VERSION 5.7 ;
  NOWIREEXTENSIONATPIN ON ;
  DIVIDERCHAR "/" ;
  BUSBITCHARS "[]" ;
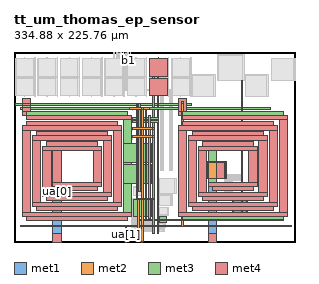
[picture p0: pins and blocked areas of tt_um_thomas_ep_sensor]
MACRO tt_um_thomas_ep_sensor
  CLASS BLOCK ;
  FOREIGN tt_um_thomas_ep_sensor ;
  ORIGIN 0.000 0.000 ;
  SIZE 334.880 BY 225.760 ;
  PIN ua[0]
    PORT
      LAYER met1 ;
        RECT 46.000 0.000 56.000 119.000 ;
        RECT 231.000 0.000 241.000 119.000 ;
      LAYER met2 ;
        RECT 145.000 160.000 147.000 164.000 ;
        RECT 148.000 160.000 150.000 164.000 ;
        RECT 137.000 158.000 161.000 160.000 ;
        RECT 15.000 150.000 135.000 155.000 ;
        RECT 15.000 145.000 140.000 150.000 ;
        RECT 15.000 138.000 123.000 143.000 ;
        RECT 10.000 133.000 128.000 138.000 ;
        RECT 10.000 35.000 20.000 133.000 ;
        RECT 27.000 126.000 111.000 131.000 ;
        RECT 22.000 121.000 116.000 126.000 ;
        RECT 22.000 47.000 32.000 121.000 ;
        RECT 39.000 114.000 99.000 119.000 ;
        RECT 34.000 109.000 104.000 114.000 ;
        RECT 34.000 59.000 44.000 109.000 ;
        RECT 46.000 71.000 56.000 109.000 ;
        RECT 94.000 71.000 104.000 109.000 ;
        RECT 46.000 66.000 104.000 71.000 ;
        RECT 51.000 61.000 99.000 66.000 ;
        RECT 106.000 59.000 116.000 121.000 ;
        RECT 34.000 54.000 116.000 59.000 ;
        RECT 39.000 49.000 111.000 54.000 ;
        RECT 118.000 47.000 128.000 133.000 ;
        RECT 22.000 42.000 128.000 47.000 ;
        RECT 27.000 37.000 123.000 42.000 ;
        RECT 130.000 35.000 140.000 145.000 ;
        RECT 145.000 136.000 147.000 158.000 ;
        RECT 148.000 136.000 150.000 158.000 ;
        RECT 151.000 136.000 153.500 158.000 ;
        RECT 156.000 136.000 158.000 156.000 ;
        RECT 199.000 155.000 201.000 167.000 ;
        RECT 270.000 155.000 272.000 192.000 ;
        RECT 199.000 150.000 320.000 155.000 ;
        RECT 160.000 136.000 162.000 150.000 ;
        RECT 199.000 145.000 325.000 150.000 ;
        RECT 199.000 143.000 201.000 145.000 ;
        RECT 270.000 143.000 272.000 145.000 ;
        RECT 199.000 138.000 308.000 143.000 ;
        RECT 141.000 134.000 167.000 136.000 ;
        RECT 145.000 126.000 147.000 134.000 ;
        RECT 148.000 126.000 150.000 134.000 ;
        RECT 151.000 126.000 153.500 134.000 ;
        RECT 156.000 126.000 158.000 134.000 ;
        RECT 160.000 126.000 162.000 134.000 ;
        RECT 195.000 133.000 313.000 138.000 ;
        RECT 141.000 124.000 167.000 126.000 ;
        RECT 145.000 52.000 147.000 124.000 ;
        RECT 148.000 60.000 150.000 124.000 ;
        RECT 145.000 50.000 149.000 52.000 ;
        RECT 10.000 30.000 140.000 35.000 ;
        RECT 15.000 25.000 135.000 30.000 ;
        RECT 42.000 18.000 60.000 20.000 ;
        RECT 147.000 14.000 149.000 50.000 ;
        RECT 46.000 0.000 56.000 10.000 ;
        RECT 151.000 1.000 153.500 124.000 ;
        RECT 156.000 28.000 158.000 124.000 ;
        RECT 160.000 52.000 162.000 124.000 ;
        RECT 159.000 50.000 167.000 52.000 ;
        RECT 160.000 28.000 162.000 50.000 ;
        RECT 195.000 35.000 205.000 133.000 ;
        RECT 270.000 131.000 272.000 133.000 ;
        RECT 212.000 126.000 296.000 131.000 ;
        RECT 207.000 121.000 301.000 126.000 ;
        RECT 207.000 47.000 217.000 121.000 ;
        RECT 270.000 119.000 272.000 121.000 ;
        RECT 224.000 114.000 284.000 119.000 ;
        RECT 219.000 109.000 289.000 114.000 ;
        RECT 219.000 59.000 229.000 109.000 ;
        RECT 231.000 71.000 241.000 109.000 ;
        RECT 270.000 71.000 272.000 109.000 ;
        RECT 279.000 71.000 289.000 109.000 ;
        RECT 231.000 66.000 289.000 71.000 ;
        RECT 236.000 61.000 284.000 66.000 ;
        RECT 270.000 59.000 272.000 61.000 ;
        RECT 291.000 59.000 301.000 121.000 ;
        RECT 219.000 54.000 301.000 59.000 ;
        RECT 224.000 49.000 296.000 54.000 ;
        RECT 270.000 47.000 272.000 49.000 ;
        RECT 303.000 47.000 313.000 133.000 ;
        RECT 207.000 42.000 313.000 47.000 ;
        RECT 212.000 37.000 308.000 42.000 ;
        RECT 270.000 35.000 272.000 37.000 ;
        RECT 315.000 35.000 325.000 145.000 ;
        RECT 195.000 30.000 325.000 35.000 ;
        RECT 199.000 25.000 320.000 30.000 ;
        RECT 170.000 18.000 198.000 20.000 ;
        RECT 199.000 18.000 201.000 25.000 ;
        RECT 222.000 18.000 240.000 20.000 ;
        RECT 151.810 0.500 152.710 1.000 ;
        RECT 231.000 0.000 241.000 10.000 ;
      LAYER met3 ;
        RECT 199.000 165.000 201.000 167.000 ;
        RECT 10.000 164.000 20.000 165.000 ;
        RECT 2.000 162.000 211.000 164.000 ;
        RECT 10.000 160.000 20.000 162.000 ;
        RECT 8.000 158.000 139.000 160.000 ;
        RECT 151.000 158.000 153.500 160.000 ;
        RECT 159.000 158.000 305.000 160.000 ;
        RECT 15.000 150.000 135.000 155.000 ;
        RECT 200.000 150.000 320.000 155.000 ;
        RECT 15.000 145.000 140.000 150.000 ;
        RECT 141.000 146.000 172.000 148.000 ;
        RECT 200.000 145.000 325.000 150.000 ;
        RECT 15.000 138.000 123.000 143.000 ;
        RECT 10.000 133.000 128.000 138.000 ;
        RECT 10.000 35.000 20.000 133.000 ;
        RECT 27.000 126.000 111.000 131.000 ;
        RECT 22.000 121.000 116.000 126.000 ;
        RECT 22.000 47.000 32.000 121.000 ;
        RECT 39.000 114.000 99.000 119.000 ;
        RECT 34.000 109.000 104.000 114.000 ;
        RECT 34.000 59.000 44.000 109.000 ;
        RECT 46.000 71.000 56.000 109.000 ;
        RECT 94.000 71.000 104.000 109.000 ;
        RECT 46.000 66.000 104.000 71.000 ;
        RECT 51.000 61.000 99.000 66.000 ;
        RECT 106.000 59.000 116.000 121.000 ;
        RECT 34.000 54.000 116.000 59.000 ;
        RECT 39.000 49.000 111.000 54.000 ;
        RECT 118.000 47.000 128.000 133.000 ;
        RECT 22.000 42.000 128.000 47.000 ;
        RECT 130.000 117.400 140.000 145.000 ;
        RECT 141.000 142.000 172.000 144.000 ;
        RECT 200.000 138.000 308.000 143.000 ;
        RECT 165.000 134.000 167.000 136.000 ;
        RECT 195.000 133.000 313.000 138.000 ;
        RECT 165.000 124.000 167.000 126.000 ;
        RECT 130.000 95.000 164.160 117.400 ;
        RECT 130.000 92.400 140.000 95.000 ;
        RECT 130.000 70.000 164.160 92.400 ;
        RECT 27.000 37.000 123.000 42.000 ;
        RECT 130.000 35.000 140.000 70.000 ;
        RECT 147.000 50.600 161.000 52.000 ;
        RECT 10.000 30.000 140.000 35.000 ;
        RECT 142.000 30.000 164.360 50.600 ;
        RECT 165.000 50.000 167.000 52.000 ;
        RECT 195.000 35.000 205.000 133.000 ;
        RECT 212.000 126.000 296.000 131.000 ;
        RECT 207.000 121.000 301.000 126.000 ;
        RECT 207.000 47.000 217.000 121.000 ;
        RECT 224.000 114.000 284.000 119.000 ;
        RECT 219.000 109.000 289.000 114.000 ;
        RECT 219.000 59.000 229.000 109.000 ;
        RECT 231.000 95.400 241.000 109.000 ;
        RECT 230.000 75.000 252.160 95.400 ;
        RECT 231.000 71.000 241.000 75.000 ;
        RECT 279.000 71.000 289.000 109.000 ;
        RECT 231.000 66.000 289.000 71.000 ;
        RECT 236.000 61.000 284.000 66.000 ;
        RECT 291.000 59.000 301.000 121.000 ;
        RECT 219.000 54.000 301.000 59.000 ;
        RECT 224.000 49.000 296.000 54.000 ;
        RECT 260.000 47.000 277.960 49.000 ;
        RECT 303.000 47.000 313.000 133.000 ;
        RECT 207.000 42.000 313.000 47.000 ;
        RECT 212.000 37.000 308.000 42.000 ;
        RECT 260.000 35.000 277.960 37.000 ;
        RECT 315.000 35.000 325.000 145.000 ;
        RECT 15.000 25.000 135.000 30.000 ;
        RECT 173.000 27.000 181.480 30.350 ;
        RECT 195.000 30.000 325.000 35.000 ;
        RECT 200.000 27.000 320.000 30.000 ;
        RECT 148.000 25.000 320.000 27.000 ;
        RECT 173.000 23.630 181.480 25.000 ;
        RECT 8.000 18.000 44.000 20.000 ;
        RECT 58.000 18.000 172.000 20.000 ;
        RECT 196.000 18.000 224.000 20.000 ;
        RECT 238.000 18.000 330.000 20.000 ;
        RECT 46.000 0.000 56.000 10.000 ;
        RECT 132.500 1.000 133.500 18.000 ;
        RECT 132.490 0.500 133.390 1.000 ;
        RECT 151.810 0.500 152.710 1.000 ;
        RECT 231.000 0.000 241.000 10.000 ;
      LAYER met4 ;
        RECT 171.380 217.805 171.900 219.000 ;
        RECT 161.335 197.195 181.945 217.805 ;
        RECT 165.000 194.805 167.000 197.195 ;
        RECT 170.000 194.805 172.000 197.195 ;
        RECT 161.335 174.195 181.945 194.805 ;
        RECT 10.000 155.000 20.000 170.000 ;
        RECT 10.000 150.000 135.000 155.000 ;
        RECT 15.000 145.000 140.000 150.000 ;
        RECT 15.000 138.000 123.000 143.000 ;
        RECT 10.000 133.000 128.000 138.000 ;
        RECT 10.000 35.000 20.000 133.000 ;
        RECT 27.000 126.000 111.000 131.000 ;
        RECT 22.000 121.000 116.000 126.000 ;
        RECT 22.000 47.000 32.000 121.000 ;
        RECT 39.000 114.000 99.000 119.000 ;
        RECT 34.000 109.000 104.000 114.000 ;
        RECT 34.000 59.000 44.000 109.000 ;
        RECT 46.000 71.000 56.000 109.000 ;
        RECT 94.000 71.000 104.000 109.000 ;
        RECT 46.000 66.000 104.000 71.000 ;
        RECT 51.000 61.000 99.000 66.000 ;
        RECT 106.000 59.000 116.000 121.000 ;
        RECT 34.000 54.000 116.000 59.000 ;
        RECT 39.000 49.000 111.000 54.000 ;
        RECT 118.000 47.000 128.000 133.000 ;
        RECT 22.000 42.000 128.000 47.000 ;
        RECT 27.000 37.000 123.000 42.000 ;
        RECT 130.000 35.000 140.000 145.000 ;
        RECT 163.660 95.060 164.140 117.340 ;
        RECT 163.660 70.060 164.140 92.340 ;
        RECT 10.000 30.000 140.000 35.000 ;
        RECT 163.860 30.060 164.340 50.540 ;
        RECT 15.000 25.000 135.000 30.000 ;
        RECT 165.000 10.000 167.000 174.195 ;
        RECT 170.000 10.000 172.000 174.195 ;
        RECT 195.000 155.000 205.000 170.000 ;
        RECT 195.000 150.000 320.000 155.000 ;
        RECT 200.000 145.000 325.000 150.000 ;
        RECT 200.000 138.000 308.000 143.000 ;
        RECT 195.000 133.000 313.000 138.000 ;
        RECT 195.000 35.000 205.000 133.000 ;
        RECT 212.000 126.000 296.000 131.000 ;
        RECT 207.000 121.000 301.000 126.000 ;
        RECT 207.000 47.000 217.000 121.000 ;
        RECT 224.000 114.000 284.000 119.000 ;
        RECT 219.000 109.000 289.000 114.000 ;
        RECT 219.000 59.000 229.000 109.000 ;
        RECT 231.000 95.005 241.000 109.000 ;
        RECT 230.395 75.395 250.005 95.005 ;
        RECT 231.000 71.000 241.000 75.395 ;
        RECT 251.660 75.060 252.140 95.340 ;
        RECT 279.000 71.000 289.000 109.000 ;
        RECT 231.000 66.000 289.000 71.000 ;
        RECT 236.000 61.000 284.000 66.000 ;
        RECT 291.000 59.000 301.000 121.000 ;
        RECT 219.000 54.000 301.000 59.000 ;
        RECT 224.000 49.000 296.000 54.000 ;
        RECT 260.395 47.000 275.805 49.000 ;
        RECT 277.460 47.000 277.940 49.000 ;
        RECT 303.000 47.000 313.000 133.000 ;
        RECT 207.000 42.000 313.000 47.000 ;
        RECT 212.000 37.000 308.000 42.000 ;
        RECT 260.395 35.395 275.805 37.000 ;
        RECT 277.460 35.060 277.940 37.000 ;
        RECT 315.000 35.000 325.000 145.000 ;
        RECT 180.980 23.690 181.460 30.290 ;
        RECT 195.000 30.000 325.000 35.000 ;
        RECT 200.000 25.000 320.000 30.000 ;
        RECT 46.000 0.000 56.000 10.000 ;
        RECT 132.490 0.000 133.390 1.000 ;
        RECT 151.810 0.000 152.710 1.000 ;
        RECT 231.000 0.000 241.000 10.000 ;
    END
  END ua[0]
  PIN ua[1]
    PORT
      LAYER met4 ;
        RECT 132.490 0.000 133.390 1.000 ;
    END
  END ua[1]
  PIN b0
    PORT
      LAYER met4 ;
        RECT 138.310 224.760 138.610 225.760 ;
    END
  END b0
  PIN b1
    PORT
      LAYER met4 ;
        RECT 135.550 224.760 135.850 225.760 ;
    END
  END b1
  PIN b2
    PORT
      LAYER met4 ;
        RECT 132.790 224.760 133.090 225.760 ;
    END
  END b2
  PIN b3
    PORT
      LAYER met4 ;
        RECT 130.030 224.760 130.330 225.760 ;
    END
  END b3
  PIN b4
    PORT
      LAYER met4 ;
        RECT 127.270 224.760 127.570 225.760 ;
    END
  END b4
  PIN b5
    PORT
      LAYER met4 ;
        RECT 124.510 224.760 124.810 225.760 ;
    END
  END b5
  PIN b6
    PORT
      LAYER met4 ;
        RECT 121.750 224.760 122.050 225.760 ;
    END
  END b6
  PIN b7
    PORT
      LAYER met4 ;
        RECT 118.990 224.760 119.290 225.760 ;
    END
  END b7
  OBS
      LAYER pwell ;
        RECT 174.000 85.000 177.590 173.100 ;
        RECT 185.000 85.000 188.590 173.100 ;
        RECT 250.000 73.000 270.870 80.100 ;
        RECT 250.000 60.000 259.570 72.100 ;
        RECT 140.000 12.000 147.100 52.070 ;
        RECT 148.000 12.000 165.470 24.100 ;
      LAYER li1 ;
        RECT 174.180 172.750 177.410 172.920 ;
        RECT 141.000 156.000 141.350 158.160 ;
        RECT 156.770 156.000 157.120 158.160 ;
        RECT 174.180 151.350 174.350 172.750 ;
        RECT 175.390 172.240 175.720 172.410 ;
        RECT 176.350 172.240 176.680 172.410 ;
        RECT 174.750 152.030 174.920 172.070 ;
        RECT 175.230 152.030 175.400 172.070 ;
        RECT 175.710 152.030 175.880 172.070 ;
        RECT 176.190 152.030 176.360 172.070 ;
        RECT 176.670 152.030 176.840 172.070 ;
        RECT 174.910 151.690 175.240 151.860 ;
        RECT 175.870 151.690 176.200 151.860 ;
        RECT 177.240 151.350 177.410 172.750 ;
        RECT 174.180 151.180 177.410 151.350 ;
        RECT 185.180 172.750 188.410 172.920 ;
        RECT 185.180 151.350 185.350 172.750 ;
        RECT 186.390 172.240 186.720 172.410 ;
        RECT 187.350 172.240 187.680 172.410 ;
        RECT 185.750 152.030 185.920 172.070 ;
        RECT 186.230 152.030 186.400 172.070 ;
        RECT 186.710 152.030 186.880 172.070 ;
        RECT 187.190 152.030 187.360 172.070 ;
        RECT 187.670 152.030 187.840 172.070 ;
        RECT 185.910 151.690 186.240 151.860 ;
        RECT 186.870 151.690 187.200 151.860 ;
        RECT 188.240 151.350 188.410 172.750 ;
        RECT 185.180 151.180 188.410 151.350 ;
        RECT 174.180 150.750 177.410 150.920 ;
        RECT 141.000 144.000 141.350 146.160 ;
        RECT 153.450 144.000 153.800 146.160 ;
        RECT 141.000 132.000 141.350 134.160 ;
        RECT 148.470 132.000 148.820 134.160 ;
        RECT 174.180 129.350 174.350 150.750 ;
        RECT 175.390 150.240 175.720 150.410 ;
        RECT 176.350 150.240 176.680 150.410 ;
        RECT 174.750 130.030 174.920 150.070 ;
        RECT 175.230 130.030 175.400 150.070 ;
        RECT 175.710 130.030 175.880 150.070 ;
        RECT 176.190 130.030 176.360 150.070 ;
        RECT 176.670 130.030 176.840 150.070 ;
        RECT 174.910 129.690 175.240 129.860 ;
        RECT 175.870 129.690 176.200 129.860 ;
        RECT 177.240 129.350 177.410 150.750 ;
        RECT 174.180 129.180 177.410 129.350 ;
        RECT 185.180 150.750 188.410 150.920 ;
        RECT 185.180 129.350 185.350 150.750 ;
        RECT 186.390 150.240 186.720 150.410 ;
        RECT 187.350 150.240 187.680 150.410 ;
        RECT 185.750 130.030 185.920 150.070 ;
        RECT 186.230 130.030 186.400 150.070 ;
        RECT 186.710 130.030 186.880 150.070 ;
        RECT 187.190 130.030 187.360 150.070 ;
        RECT 187.670 130.030 187.840 150.070 ;
        RECT 185.910 129.690 186.240 129.860 ;
        RECT 186.870 129.690 187.200 129.860 ;
        RECT 188.240 129.350 188.410 150.750 ;
        RECT 185.180 129.180 188.410 129.350 ;
        RECT 174.180 128.750 177.410 128.920 ;
        RECT 141.000 122.000 141.350 124.160 ;
        RECT 146.810 122.000 147.160 124.160 ;
        RECT 174.180 107.350 174.350 128.750 ;
        RECT 175.390 128.240 175.720 128.410 ;
        RECT 176.350 128.240 176.680 128.410 ;
        RECT 174.750 108.030 174.920 128.070 ;
        RECT 175.230 108.030 175.400 128.070 ;
        RECT 175.710 108.030 175.880 128.070 ;
        RECT 176.190 108.030 176.360 128.070 ;
        RECT 176.670 108.030 176.840 128.070 ;
        RECT 174.910 107.690 175.240 107.860 ;
        RECT 175.870 107.690 176.200 107.860 ;
        RECT 177.240 107.350 177.410 128.750 ;
        RECT 174.180 107.180 177.410 107.350 ;
        RECT 185.180 128.750 188.410 128.920 ;
        RECT 185.180 107.350 185.350 128.750 ;
        RECT 186.390 128.240 186.720 128.410 ;
        RECT 187.350 128.240 187.680 128.410 ;
        RECT 185.750 108.030 185.920 128.070 ;
        RECT 186.230 108.030 186.400 128.070 ;
        RECT 186.710 108.030 186.880 128.070 ;
        RECT 187.190 108.030 187.360 128.070 ;
        RECT 187.670 108.030 187.840 128.070 ;
        RECT 185.910 107.690 186.240 107.860 ;
        RECT 186.870 107.690 187.200 107.860 ;
        RECT 188.240 107.350 188.410 128.750 ;
        RECT 185.180 107.180 188.410 107.350 ;
        RECT 174.180 106.750 177.410 106.920 ;
        RECT 174.180 85.350 174.350 106.750 ;
        RECT 175.390 106.240 175.720 106.410 ;
        RECT 176.350 106.240 176.680 106.410 ;
        RECT 174.750 86.030 174.920 106.070 ;
        RECT 175.230 86.030 175.400 106.070 ;
        RECT 175.710 86.030 175.880 106.070 ;
        RECT 176.190 86.030 176.360 106.070 ;
        RECT 176.670 86.030 176.840 106.070 ;
        RECT 174.910 85.690 175.240 85.860 ;
        RECT 175.870 85.690 176.200 85.860 ;
        RECT 177.240 85.350 177.410 106.750 ;
        RECT 174.180 85.180 177.410 85.350 ;
        RECT 185.180 106.750 188.410 106.920 ;
        RECT 185.180 85.350 185.350 106.750 ;
        RECT 186.390 106.240 186.720 106.410 ;
        RECT 187.350 106.240 187.680 106.410 ;
        RECT 185.750 86.030 185.920 106.070 ;
        RECT 186.230 86.030 186.400 106.070 ;
        RECT 186.710 86.030 186.880 106.070 ;
        RECT 187.190 86.030 187.360 106.070 ;
        RECT 187.670 86.030 187.840 106.070 ;
        RECT 185.910 85.690 186.240 85.860 ;
        RECT 186.870 85.690 187.200 85.860 ;
        RECT 188.240 85.350 188.410 106.750 ;
        RECT 185.180 85.180 188.410 85.350 ;
        RECT 250.180 79.750 270.690 79.920 ;
        RECT 250.180 73.350 250.350 79.750 ;
        RECT 251.390 79.240 251.720 79.410 ;
        RECT 252.350 79.240 252.680 79.410 ;
        RECT 253.310 79.240 253.640 79.410 ;
        RECT 254.270 79.240 254.600 79.410 ;
        RECT 255.230 79.240 255.560 79.410 ;
        RECT 256.190 79.240 256.520 79.410 ;
        RECT 257.150 79.240 257.480 79.410 ;
        RECT 258.110 79.240 258.440 79.410 ;
        RECT 259.070 79.240 259.400 79.410 ;
        RECT 260.030 79.240 260.360 79.410 ;
        RECT 260.990 79.240 261.320 79.410 ;
        RECT 261.950 79.240 262.280 79.410 ;
        RECT 262.910 79.240 263.240 79.410 ;
        RECT 263.870 79.240 264.200 79.410 ;
        RECT 264.830 79.240 265.160 79.410 ;
        RECT 265.790 79.240 266.120 79.410 ;
        RECT 266.750 79.240 267.080 79.410 ;
        RECT 267.710 79.240 268.040 79.410 ;
        RECT 268.670 79.240 269.000 79.410 ;
        RECT 269.630 79.240 269.960 79.410 ;
        RECT 250.750 74.030 250.920 79.070 ;
        RECT 251.230 74.030 251.400 79.070 ;
        RECT 251.710 74.030 251.880 79.070 ;
        RECT 252.190 74.030 252.360 79.070 ;
        RECT 252.670 74.030 252.840 79.070 ;
        RECT 253.150 74.030 253.320 79.070 ;
        RECT 253.630 74.030 253.800 79.070 ;
        RECT 254.110 74.030 254.280 79.070 ;
        RECT 254.590 74.030 254.760 79.070 ;
        RECT 255.070 74.030 255.240 79.070 ;
        RECT 255.550 74.030 255.720 79.070 ;
        RECT 256.030 74.030 256.200 79.070 ;
        RECT 256.510 74.030 256.680 79.070 ;
        RECT 256.990 74.030 257.160 79.070 ;
        RECT 257.470 74.030 257.640 79.070 ;
        RECT 257.950 74.030 258.120 79.070 ;
        RECT 258.430 74.030 258.600 79.070 ;
        RECT 258.910 74.030 259.080 79.070 ;
        RECT 259.390 74.030 259.560 79.070 ;
        RECT 259.870 74.030 260.040 79.070 ;
        RECT 260.350 74.030 260.520 79.070 ;
        RECT 260.830 74.030 261.000 79.070 ;
        RECT 261.310 74.030 261.480 79.070 ;
        RECT 261.790 74.030 261.960 79.070 ;
        RECT 262.270 74.030 262.440 79.070 ;
        RECT 262.750 74.030 262.920 79.070 ;
        RECT 263.230 74.030 263.400 79.070 ;
        RECT 263.710 74.030 263.880 79.070 ;
        RECT 264.190 74.030 264.360 79.070 ;
        RECT 264.670 74.030 264.840 79.070 ;
        RECT 265.150 74.030 265.320 79.070 ;
        RECT 265.630 74.030 265.800 79.070 ;
        RECT 266.110 74.030 266.280 79.070 ;
        RECT 266.590 74.030 266.760 79.070 ;
        RECT 267.070 74.030 267.240 79.070 ;
        RECT 267.550 74.030 267.720 79.070 ;
        RECT 268.030 74.030 268.200 79.070 ;
        RECT 268.510 74.030 268.680 79.070 ;
        RECT 268.990 74.030 269.160 79.070 ;
        RECT 269.470 74.030 269.640 79.070 ;
        RECT 269.950 74.030 270.120 79.070 ;
        RECT 250.910 73.690 251.240 73.860 ;
        RECT 251.870 73.690 252.200 73.860 ;
        RECT 252.830 73.690 253.160 73.860 ;
        RECT 253.790 73.690 254.120 73.860 ;
        RECT 254.750 73.690 255.080 73.860 ;
        RECT 255.710 73.690 256.040 73.860 ;
        RECT 256.670 73.690 257.000 73.860 ;
        RECT 257.630 73.690 257.960 73.860 ;
        RECT 258.590 73.690 258.920 73.860 ;
        RECT 259.550 73.690 259.880 73.860 ;
        RECT 260.510 73.690 260.840 73.860 ;
        RECT 261.470 73.690 261.800 73.860 ;
        RECT 262.430 73.690 262.760 73.860 ;
        RECT 263.390 73.690 263.720 73.860 ;
        RECT 264.350 73.690 264.680 73.860 ;
        RECT 265.310 73.690 265.640 73.860 ;
        RECT 266.270 73.690 266.600 73.860 ;
        RECT 267.230 73.690 267.560 73.860 ;
        RECT 268.190 73.690 268.520 73.860 ;
        RECT 269.150 73.690 269.480 73.860 ;
        RECT 270.520 73.350 270.690 79.750 ;
        RECT 250.180 73.180 270.690 73.350 ;
        RECT 250.180 71.750 259.390 71.920 ;
        RECT 250.180 60.350 250.350 71.750 ;
        RECT 250.980 71.240 251.480 71.410 ;
        RECT 251.770 71.240 252.270 71.410 ;
        RECT 252.560 71.240 253.060 71.410 ;
        RECT 253.350 71.240 253.850 71.410 ;
        RECT 254.140 71.240 254.640 71.410 ;
        RECT 254.930 71.240 255.430 71.410 ;
        RECT 255.720 71.240 256.220 71.410 ;
        RECT 256.510 71.240 257.010 71.410 ;
        RECT 257.300 71.240 257.800 71.410 ;
        RECT 258.090 71.240 258.590 71.410 ;
        RECT 250.750 61.030 250.920 71.070 ;
        RECT 251.540 61.030 251.710 71.070 ;
        RECT 252.330 61.030 252.500 71.070 ;
        RECT 253.120 61.030 253.290 71.070 ;
        RECT 253.910 61.030 254.080 71.070 ;
        RECT 254.700 61.030 254.870 71.070 ;
        RECT 255.490 61.030 255.660 71.070 ;
        RECT 256.280 61.030 256.450 71.070 ;
        RECT 257.070 61.030 257.240 71.070 ;
        RECT 257.860 61.030 258.030 71.070 ;
        RECT 258.650 61.030 258.820 71.070 ;
        RECT 250.980 60.690 251.480 60.860 ;
        RECT 251.770 60.690 252.270 60.860 ;
        RECT 252.560 60.690 253.060 60.860 ;
        RECT 253.350 60.690 253.850 60.860 ;
        RECT 254.140 60.690 254.640 60.860 ;
        RECT 254.930 60.690 255.430 60.860 ;
        RECT 255.720 60.690 256.220 60.860 ;
        RECT 256.510 60.690 257.010 60.860 ;
        RECT 257.300 60.690 257.800 60.860 ;
        RECT 258.090 60.690 258.590 60.860 ;
        RECT 259.220 60.350 259.390 71.750 ;
        RECT 280.000 65.000 280.350 67.160 ;
        RECT 290.790 65.000 291.140 67.160 ;
        RECT 250.180 60.180 259.390 60.350 ;
        RECT 140.180 51.720 146.920 51.890 ;
        RECT 140.180 12.350 140.350 51.720 ;
        RECT 140.690 50.830 140.860 51.160 ;
        RECT 141.030 51.150 146.070 51.320 ;
        RECT 141.030 50.670 146.070 50.840 ;
        RECT 140.690 49.870 140.860 50.200 ;
        RECT 141.030 50.190 146.070 50.360 ;
        RECT 146.240 50.350 146.410 50.680 ;
        RECT 141.030 49.710 146.070 49.880 ;
        RECT 140.690 48.910 140.860 49.240 ;
        RECT 141.030 49.230 146.070 49.400 ;
        RECT 146.240 49.390 146.410 49.720 ;
        RECT 141.030 48.750 146.070 48.920 ;
        RECT 140.690 47.950 140.860 48.280 ;
        RECT 141.030 48.270 146.070 48.440 ;
        RECT 146.240 48.430 146.410 48.760 ;
        RECT 141.030 47.790 146.070 47.960 ;
        RECT 140.690 46.990 140.860 47.320 ;
        RECT 141.030 47.310 146.070 47.480 ;
        RECT 146.240 47.470 146.410 47.800 ;
        RECT 141.030 46.830 146.070 47.000 ;
        RECT 140.690 46.030 140.860 46.360 ;
        RECT 141.030 46.350 146.070 46.520 ;
        RECT 146.240 46.510 146.410 46.840 ;
        RECT 141.030 45.870 146.070 46.040 ;
        RECT 140.690 45.070 140.860 45.400 ;
        RECT 141.030 45.390 146.070 45.560 ;
        RECT 146.240 45.550 146.410 45.880 ;
        RECT 141.030 44.910 146.070 45.080 ;
        RECT 140.690 44.110 140.860 44.440 ;
        RECT 141.030 44.430 146.070 44.600 ;
        RECT 146.240 44.590 146.410 44.920 ;
        RECT 141.030 43.950 146.070 44.120 ;
        RECT 140.690 43.150 140.860 43.480 ;
        RECT 141.030 43.470 146.070 43.640 ;
        RECT 146.240 43.630 146.410 43.960 ;
        RECT 141.030 42.990 146.070 43.160 ;
        RECT 140.690 42.190 140.860 42.520 ;
        RECT 141.030 42.510 146.070 42.680 ;
        RECT 146.240 42.670 146.410 43.000 ;
        RECT 141.030 42.030 146.070 42.200 ;
        RECT 140.690 41.230 140.860 41.560 ;
        RECT 141.030 41.550 146.070 41.720 ;
        RECT 146.240 41.710 146.410 42.040 ;
        RECT 141.030 41.070 146.070 41.240 ;
        RECT 140.690 40.270 140.860 40.600 ;
        RECT 141.030 40.590 146.070 40.760 ;
        RECT 146.240 40.750 146.410 41.080 ;
        RECT 141.030 40.110 146.070 40.280 ;
        RECT 140.690 39.310 140.860 39.640 ;
        RECT 141.030 39.630 146.070 39.800 ;
        RECT 146.240 39.790 146.410 40.120 ;
        RECT 141.030 39.150 146.070 39.320 ;
        RECT 140.690 38.350 140.860 38.680 ;
        RECT 141.030 38.670 146.070 38.840 ;
        RECT 146.240 38.830 146.410 39.160 ;
        RECT 141.030 38.190 146.070 38.360 ;
        RECT 140.690 37.390 140.860 37.720 ;
        RECT 141.030 37.710 146.070 37.880 ;
        RECT 146.240 37.870 146.410 38.200 ;
        RECT 141.030 37.230 146.070 37.400 ;
        RECT 140.690 36.430 140.860 36.760 ;
        RECT 141.030 36.750 146.070 36.920 ;
        RECT 146.240 36.910 146.410 37.240 ;
        RECT 141.030 36.270 146.070 36.440 ;
        RECT 140.690 35.470 140.860 35.800 ;
        RECT 141.030 35.790 146.070 35.960 ;
        RECT 146.240 35.950 146.410 36.280 ;
        RECT 141.030 35.310 146.070 35.480 ;
        RECT 140.690 34.510 140.860 34.840 ;
        RECT 141.030 34.830 146.070 35.000 ;
        RECT 146.240 34.990 146.410 35.320 ;
        RECT 141.030 34.350 146.070 34.520 ;
        RECT 140.690 33.550 140.860 33.880 ;
        RECT 141.030 33.870 146.070 34.040 ;
        RECT 146.240 34.030 146.410 34.360 ;
        RECT 141.030 33.390 146.070 33.560 ;
        RECT 140.690 32.590 140.860 32.920 ;
        RECT 141.030 32.910 146.070 33.080 ;
        RECT 146.240 33.070 146.410 33.400 ;
        RECT 141.030 32.430 146.070 32.600 ;
        RECT 140.690 31.630 140.860 31.960 ;
        RECT 141.030 31.950 146.070 32.120 ;
        RECT 146.240 32.110 146.410 32.440 ;
        RECT 141.030 31.470 146.070 31.640 ;
        RECT 140.690 30.670 140.860 31.000 ;
        RECT 141.030 30.990 146.070 31.160 ;
        RECT 146.240 31.150 146.410 31.480 ;
        RECT 141.030 30.510 146.070 30.680 ;
        RECT 140.690 29.710 140.860 30.040 ;
        RECT 141.030 30.030 146.070 30.200 ;
        RECT 146.240 30.190 146.410 30.520 ;
        RECT 141.030 29.550 146.070 29.720 ;
        RECT 140.690 28.750 140.860 29.080 ;
        RECT 141.030 29.070 146.070 29.240 ;
        RECT 146.240 29.230 146.410 29.560 ;
        RECT 141.030 28.590 146.070 28.760 ;
        RECT 140.690 27.790 140.860 28.120 ;
        RECT 141.030 28.110 146.070 28.280 ;
        RECT 146.240 28.270 146.410 28.600 ;
        RECT 141.030 27.630 146.070 27.800 ;
        RECT 140.690 26.830 140.860 27.160 ;
        RECT 141.030 27.150 146.070 27.320 ;
        RECT 146.240 27.310 146.410 27.640 ;
        RECT 141.030 26.670 146.070 26.840 ;
        RECT 140.690 25.870 140.860 26.200 ;
        RECT 141.030 26.190 146.070 26.360 ;
        RECT 146.240 26.350 146.410 26.680 ;
        RECT 141.030 25.710 146.070 25.880 ;
        RECT 140.690 24.910 140.860 25.240 ;
        RECT 141.030 25.230 146.070 25.400 ;
        RECT 146.240 25.390 146.410 25.720 ;
        RECT 141.030 24.750 146.070 24.920 ;
        RECT 140.690 23.950 140.860 24.280 ;
        RECT 141.030 24.270 146.070 24.440 ;
        RECT 146.240 24.430 146.410 24.760 ;
        RECT 141.030 23.790 146.070 23.960 ;
        RECT 140.690 22.990 140.860 23.320 ;
        RECT 141.030 23.310 146.070 23.480 ;
        RECT 146.240 23.470 146.410 23.800 ;
        RECT 141.030 22.830 146.070 23.000 ;
        RECT 140.690 22.030 140.860 22.360 ;
        RECT 141.030 22.350 146.070 22.520 ;
        RECT 146.240 22.510 146.410 22.840 ;
        RECT 141.030 21.870 146.070 22.040 ;
        RECT 140.690 21.070 140.860 21.400 ;
        RECT 141.030 21.390 146.070 21.560 ;
        RECT 146.240 21.550 146.410 21.880 ;
        RECT 141.030 20.910 146.070 21.080 ;
        RECT 140.690 20.110 140.860 20.440 ;
        RECT 141.030 20.430 146.070 20.600 ;
        RECT 146.240 20.590 146.410 20.920 ;
        RECT 141.030 19.950 146.070 20.120 ;
        RECT 140.690 19.150 140.860 19.480 ;
        RECT 141.030 19.470 146.070 19.640 ;
        RECT 146.240 19.630 146.410 19.960 ;
        RECT 141.030 18.990 146.070 19.160 ;
        RECT 140.690 18.190 140.860 18.520 ;
        RECT 141.030 18.510 146.070 18.680 ;
        RECT 146.240 18.670 146.410 19.000 ;
        RECT 141.030 18.030 146.070 18.200 ;
        RECT 140.690 17.230 140.860 17.560 ;
        RECT 141.030 17.550 146.070 17.720 ;
        RECT 146.240 17.710 146.410 18.040 ;
        RECT 141.030 17.070 146.070 17.240 ;
        RECT 140.690 16.270 140.860 16.600 ;
        RECT 141.030 16.590 146.070 16.760 ;
        RECT 146.240 16.750 146.410 17.080 ;
        RECT 141.030 16.110 146.070 16.280 ;
        RECT 140.690 15.310 140.860 15.640 ;
        RECT 141.030 15.630 146.070 15.800 ;
        RECT 146.240 15.790 146.410 16.120 ;
        RECT 141.030 15.150 146.070 15.320 ;
        RECT 140.690 14.350 140.860 14.680 ;
        RECT 141.030 14.670 146.070 14.840 ;
        RECT 146.240 14.830 146.410 15.160 ;
        RECT 141.030 14.190 146.070 14.360 ;
        RECT 140.690 13.390 140.860 13.720 ;
        RECT 141.030 13.710 146.070 13.880 ;
        RECT 146.240 13.870 146.410 14.200 ;
        RECT 141.030 13.230 146.070 13.400 ;
        RECT 141.030 12.750 146.070 12.920 ;
        RECT 146.240 12.910 146.410 13.240 ;
        RECT 146.750 12.350 146.920 51.720 ;
        RECT 280.000 50.000 280.350 52.160 ;
        RECT 292.450 50.000 292.800 52.160 ;
        RECT 140.180 12.180 146.920 12.350 ;
        RECT 148.180 23.750 165.290 23.920 ;
        RECT 148.180 12.350 148.350 23.750 ;
        RECT 148.980 23.240 149.480 23.410 ;
        RECT 149.770 23.240 150.270 23.410 ;
        RECT 150.560 23.240 151.060 23.410 ;
        RECT 151.350 23.240 151.850 23.410 ;
        RECT 152.140 23.240 152.640 23.410 ;
        RECT 152.930 23.240 153.430 23.410 ;
        RECT 153.720 23.240 154.220 23.410 ;
        RECT 154.510 23.240 155.010 23.410 ;
        RECT 155.300 23.240 155.800 23.410 ;
        RECT 156.090 23.240 156.590 23.410 ;
        RECT 156.880 23.240 157.380 23.410 ;
        RECT 157.670 23.240 158.170 23.410 ;
        RECT 158.460 23.240 158.960 23.410 ;
        RECT 159.250 23.240 159.750 23.410 ;
        RECT 160.040 23.240 160.540 23.410 ;
        RECT 160.830 23.240 161.330 23.410 ;
        RECT 161.620 23.240 162.120 23.410 ;
        RECT 162.410 23.240 162.910 23.410 ;
        RECT 163.200 23.240 163.700 23.410 ;
        RECT 163.990 23.240 164.490 23.410 ;
        RECT 148.750 13.030 148.920 23.070 ;
        RECT 149.540 13.030 149.710 23.070 ;
        RECT 150.330 13.030 150.500 23.070 ;
        RECT 151.120 13.030 151.290 23.070 ;
        RECT 151.910 13.030 152.080 23.070 ;
        RECT 152.700 13.030 152.870 23.070 ;
        RECT 153.490 13.030 153.660 23.070 ;
        RECT 154.280 13.030 154.450 23.070 ;
        RECT 155.070 13.030 155.240 23.070 ;
        RECT 155.860 13.030 156.030 23.070 ;
        RECT 156.650 13.030 156.820 23.070 ;
        RECT 157.440 13.030 157.610 23.070 ;
        RECT 158.230 13.030 158.400 23.070 ;
        RECT 159.020 13.030 159.190 23.070 ;
        RECT 159.810 13.030 159.980 23.070 ;
        RECT 160.600 13.030 160.770 23.070 ;
        RECT 161.390 13.030 161.560 23.070 ;
        RECT 162.180 13.030 162.350 23.070 ;
        RECT 162.970 13.030 163.140 23.070 ;
        RECT 163.760 13.030 163.930 23.070 ;
        RECT 164.550 13.030 164.720 23.070 ;
        RECT 148.980 12.690 149.480 12.860 ;
        RECT 149.770 12.690 150.270 12.860 ;
        RECT 150.560 12.690 151.060 12.860 ;
        RECT 151.350 12.690 151.850 12.860 ;
        RECT 152.140 12.690 152.640 12.860 ;
        RECT 152.930 12.690 153.430 12.860 ;
        RECT 153.720 12.690 154.220 12.860 ;
        RECT 154.510 12.690 155.010 12.860 ;
        RECT 155.300 12.690 155.800 12.860 ;
        RECT 156.090 12.690 156.590 12.860 ;
        RECT 156.880 12.690 157.380 12.860 ;
        RECT 157.670 12.690 158.170 12.860 ;
        RECT 158.460 12.690 158.960 12.860 ;
        RECT 159.250 12.690 159.750 12.860 ;
        RECT 160.040 12.690 160.540 12.860 ;
        RECT 160.830 12.690 161.330 12.860 ;
        RECT 161.620 12.690 162.120 12.860 ;
        RECT 162.410 12.690 162.910 12.860 ;
        RECT 163.200 12.690 163.700 12.860 ;
        RECT 163.990 12.690 164.490 12.860 ;
        RECT 165.120 12.350 165.290 23.750 ;
        RECT 148.180 12.180 165.290 12.350 ;
      LAYER met1 ;
        RECT 175.410 172.210 175.700 172.440 ;
        RECT 176.370 172.210 176.660 172.440 ;
        RECT 186.410 172.210 186.700 172.440 ;
        RECT 187.370 172.210 187.660 172.440 ;
        RECT 141.050 156.030 141.300 158.135 ;
        RECT 156.820 156.030 157.070 158.135 ;
        RECT 174.720 152.050 174.950 172.050 ;
        RECT 175.200 152.050 175.430 172.050 ;
        RECT 175.680 152.050 175.910 172.050 ;
        RECT 176.160 152.050 176.390 172.050 ;
        RECT 176.640 152.050 176.870 172.050 ;
        RECT 185.720 152.050 185.950 172.050 ;
        RECT 186.200 152.050 186.430 172.050 ;
        RECT 186.680 152.050 186.910 172.050 ;
        RECT 187.160 152.050 187.390 172.050 ;
        RECT 187.640 152.050 187.870 172.050 ;
        RECT 174.930 151.660 175.220 151.890 ;
        RECT 175.890 151.660 176.180 151.890 ;
        RECT 185.930 151.660 186.220 151.890 ;
        RECT 186.890 151.660 187.180 151.890 ;
        RECT 175.410 150.210 175.700 150.440 ;
        RECT 176.370 150.210 176.660 150.440 ;
        RECT 186.410 150.210 186.700 150.440 ;
        RECT 187.370 150.210 187.660 150.440 ;
        RECT 141.050 144.030 141.300 146.135 ;
        RECT 153.500 144.030 153.750 146.135 ;
        RECT 141.050 132.030 141.300 134.135 ;
        RECT 148.520 132.030 148.770 134.135 ;
        RECT 174.720 130.050 174.950 150.050 ;
        RECT 175.200 130.050 175.430 150.050 ;
        RECT 175.680 130.050 175.910 150.050 ;
        RECT 176.160 130.050 176.390 150.050 ;
        RECT 176.640 130.050 176.870 150.050 ;
        RECT 185.720 130.050 185.950 150.050 ;
        RECT 186.200 130.050 186.430 150.050 ;
        RECT 186.680 130.050 186.910 150.050 ;
        RECT 187.160 130.050 187.390 150.050 ;
        RECT 187.640 130.050 187.870 150.050 ;
        RECT 174.930 129.660 175.220 129.890 ;
        RECT 175.890 129.660 176.180 129.890 ;
        RECT 185.930 129.660 186.220 129.890 ;
        RECT 186.890 129.660 187.180 129.890 ;
        RECT 175.410 128.210 175.700 128.440 ;
        RECT 176.370 128.210 176.660 128.440 ;
        RECT 186.410 128.210 186.700 128.440 ;
        RECT 187.370 128.210 187.660 128.440 ;
        RECT 141.050 122.030 141.300 124.135 ;
        RECT 146.860 122.030 147.110 124.135 ;
        RECT 174.720 108.050 174.950 128.050 ;
        RECT 175.200 108.050 175.430 128.050 ;
        RECT 175.680 108.050 175.910 128.050 ;
        RECT 176.160 108.050 176.390 128.050 ;
        RECT 176.640 108.050 176.870 128.050 ;
        RECT 185.720 108.050 185.950 128.050 ;
        RECT 186.200 108.050 186.430 128.050 ;
        RECT 186.680 108.050 186.910 128.050 ;
        RECT 187.160 108.050 187.390 128.050 ;
        RECT 187.640 108.050 187.870 128.050 ;
        RECT 174.930 107.660 175.220 107.890 ;
        RECT 175.890 107.660 176.180 107.890 ;
        RECT 185.930 107.660 186.220 107.890 ;
        RECT 186.890 107.660 187.180 107.890 ;
        RECT 175.410 106.210 175.700 106.440 ;
        RECT 176.370 106.210 176.660 106.440 ;
        RECT 186.410 106.210 186.700 106.440 ;
        RECT 187.370 106.210 187.660 106.440 ;
        RECT 174.720 86.050 174.950 106.050 ;
        RECT 175.200 86.050 175.430 106.050 ;
        RECT 175.680 86.050 175.910 106.050 ;
        RECT 176.160 86.050 176.390 106.050 ;
        RECT 176.640 86.050 176.870 106.050 ;
        RECT 185.720 86.050 185.950 106.050 ;
        RECT 186.200 86.050 186.430 106.050 ;
        RECT 186.680 86.050 186.910 106.050 ;
        RECT 187.160 86.050 187.390 106.050 ;
        RECT 187.640 86.050 187.870 106.050 ;
        RECT 174.930 85.660 175.220 85.890 ;
        RECT 175.890 85.660 176.180 85.890 ;
        RECT 185.930 85.660 186.220 85.890 ;
        RECT 186.890 85.660 187.180 85.890 ;
        RECT 251.410 79.210 251.700 79.440 ;
        RECT 252.370 79.210 252.660 79.440 ;
        RECT 253.330 79.210 253.620 79.440 ;
        RECT 254.290 79.210 254.580 79.440 ;
        RECT 255.250 79.210 255.540 79.440 ;
        RECT 256.210 79.210 256.500 79.440 ;
        RECT 257.170 79.210 257.460 79.440 ;
        RECT 258.130 79.210 258.420 79.440 ;
        RECT 259.090 79.210 259.380 79.440 ;
        RECT 260.050 79.210 260.340 79.440 ;
        RECT 261.010 79.210 261.300 79.440 ;
        RECT 261.970 79.210 262.260 79.440 ;
        RECT 262.930 79.210 263.220 79.440 ;
        RECT 263.890 79.210 264.180 79.440 ;
        RECT 264.850 79.210 265.140 79.440 ;
        RECT 265.810 79.210 266.100 79.440 ;
        RECT 266.770 79.210 267.060 79.440 ;
        RECT 267.730 79.210 268.020 79.440 ;
        RECT 268.690 79.210 268.980 79.440 ;
        RECT 269.650 79.210 269.940 79.440 ;
        RECT 250.720 74.050 250.950 79.050 ;
        RECT 251.200 74.050 251.430 79.050 ;
        RECT 251.680 74.050 251.910 79.050 ;
        RECT 252.160 74.050 252.390 79.050 ;
        RECT 252.640 74.050 252.870 79.050 ;
        RECT 253.120 74.050 253.350 79.050 ;
        RECT 253.600 74.050 253.830 79.050 ;
        RECT 254.080 74.050 254.310 79.050 ;
        RECT 254.560 74.050 254.790 79.050 ;
        RECT 255.040 74.050 255.270 79.050 ;
        RECT 255.520 74.050 255.750 79.050 ;
        RECT 256.000 74.050 256.230 79.050 ;
        RECT 256.480 74.050 256.710 79.050 ;
        RECT 256.960 74.050 257.190 79.050 ;
        RECT 257.440 74.050 257.670 79.050 ;
        RECT 257.920 74.050 258.150 79.050 ;
        RECT 258.400 74.050 258.630 79.050 ;
        RECT 258.880 74.050 259.110 79.050 ;
        RECT 259.360 74.050 259.590 79.050 ;
        RECT 259.840 74.050 260.070 79.050 ;
        RECT 260.320 74.050 260.550 79.050 ;
        RECT 260.800 74.050 261.030 79.050 ;
        RECT 261.280 74.050 261.510 79.050 ;
        RECT 261.760 74.050 261.990 79.050 ;
        RECT 262.240 74.050 262.470 79.050 ;
        RECT 262.720 74.050 262.950 79.050 ;
        RECT 263.200 74.050 263.430 79.050 ;
        RECT 263.680 74.050 263.910 79.050 ;
        RECT 264.160 74.050 264.390 79.050 ;
        RECT 264.640 74.050 264.870 79.050 ;
        RECT 265.120 74.050 265.350 79.050 ;
        RECT 265.600 74.050 265.830 79.050 ;
        RECT 266.080 74.050 266.310 79.050 ;
        RECT 266.560 74.050 266.790 79.050 ;
        RECT 267.040 74.050 267.270 79.050 ;
        RECT 267.520 74.050 267.750 79.050 ;
        RECT 268.000 74.050 268.230 79.050 ;
        RECT 268.480 74.050 268.710 79.050 ;
        RECT 268.960 74.050 269.190 79.050 ;
        RECT 269.440 74.050 269.670 79.050 ;
        RECT 269.920 74.050 270.150 79.050 ;
        RECT 250.930 73.660 251.220 73.890 ;
        RECT 251.890 73.660 252.180 73.890 ;
        RECT 252.850 73.660 253.140 73.890 ;
        RECT 253.810 73.660 254.100 73.890 ;
        RECT 254.770 73.660 255.060 73.890 ;
        RECT 255.730 73.660 256.020 73.890 ;
        RECT 256.690 73.660 256.980 73.890 ;
        RECT 257.650 73.660 257.940 73.890 ;
        RECT 258.610 73.660 258.900 73.890 ;
        RECT 259.570 73.660 259.860 73.890 ;
        RECT 260.530 73.660 260.820 73.890 ;
        RECT 261.490 73.660 261.780 73.890 ;
        RECT 262.450 73.660 262.740 73.890 ;
        RECT 263.410 73.660 263.700 73.890 ;
        RECT 264.370 73.660 264.660 73.890 ;
        RECT 265.330 73.660 265.620 73.890 ;
        RECT 266.290 73.660 266.580 73.890 ;
        RECT 267.250 73.660 267.540 73.890 ;
        RECT 268.210 73.660 268.500 73.890 ;
        RECT 269.170 73.660 269.460 73.890 ;
        RECT 251.000 71.210 251.460 71.440 ;
        RECT 251.790 71.210 252.250 71.440 ;
        RECT 252.580 71.210 253.040 71.440 ;
        RECT 253.370 71.210 253.830 71.440 ;
        RECT 254.160 71.210 254.620 71.440 ;
        RECT 254.950 71.210 255.410 71.440 ;
        RECT 255.740 71.210 256.200 71.440 ;
        RECT 256.530 71.210 256.990 71.440 ;
        RECT 257.320 71.210 257.780 71.440 ;
        RECT 258.110 71.210 258.570 71.440 ;
        RECT 250.720 61.050 250.950 71.050 ;
        RECT 251.510 61.050 251.740 71.050 ;
        RECT 252.300 61.050 252.530 71.050 ;
        RECT 253.090 61.050 253.320 71.050 ;
        RECT 253.880 61.050 254.110 71.050 ;
        RECT 254.670 61.050 254.900 71.050 ;
        RECT 255.460 61.050 255.690 71.050 ;
        RECT 256.250 61.050 256.480 71.050 ;
        RECT 257.040 61.050 257.270 71.050 ;
        RECT 257.830 61.050 258.060 71.050 ;
        RECT 258.620 61.050 258.850 71.050 ;
        RECT 280.050 65.030 280.300 67.135 ;
        RECT 290.840 65.030 291.090 67.135 ;
        RECT 251.000 60.660 251.460 60.890 ;
        RECT 251.790 60.660 252.250 60.890 ;
        RECT 252.580 60.660 253.040 60.890 ;
        RECT 253.370 60.660 253.830 60.890 ;
        RECT 254.160 60.660 254.620 60.890 ;
        RECT 254.950 60.660 255.410 60.890 ;
        RECT 255.740 60.660 256.200 60.890 ;
        RECT 256.530 60.660 256.990 60.890 ;
        RECT 257.320 60.660 257.780 60.890 ;
        RECT 258.110 60.660 258.570 60.890 ;
        RECT 140.660 50.850 140.890 51.140 ;
        RECT 141.050 51.120 146.050 51.350 ;
        RECT 141.050 50.640 146.050 50.870 ;
        RECT 140.660 49.890 140.890 50.180 ;
        RECT 141.050 50.160 146.050 50.390 ;
        RECT 146.210 50.370 146.440 50.660 ;
        RECT 280.050 50.030 280.300 52.135 ;
        RECT 292.500 50.030 292.750 52.135 ;
        RECT 141.050 49.680 146.050 49.910 ;
        RECT 140.660 48.930 140.890 49.220 ;
        RECT 141.050 49.200 146.050 49.430 ;
        RECT 146.210 49.410 146.440 49.700 ;
        RECT 141.050 48.720 146.050 48.950 ;
        RECT 140.660 47.970 140.890 48.260 ;
        RECT 141.050 48.240 146.050 48.470 ;
        RECT 146.210 48.450 146.440 48.740 ;
        RECT 141.050 47.760 146.050 47.990 ;
        RECT 140.660 47.010 140.890 47.300 ;
        RECT 141.050 47.280 146.050 47.510 ;
        RECT 146.210 47.490 146.440 47.780 ;
        RECT 141.050 46.800 146.050 47.030 ;
        RECT 140.660 46.050 140.890 46.340 ;
        RECT 141.050 46.320 146.050 46.550 ;
        RECT 146.210 46.530 146.440 46.820 ;
        RECT 141.050 45.840 146.050 46.070 ;
        RECT 140.660 45.090 140.890 45.380 ;
        RECT 141.050 45.360 146.050 45.590 ;
        RECT 146.210 45.570 146.440 45.860 ;
        RECT 141.050 44.880 146.050 45.110 ;
        RECT 140.660 44.130 140.890 44.420 ;
        RECT 141.050 44.400 146.050 44.630 ;
        RECT 146.210 44.610 146.440 44.900 ;
        RECT 141.050 43.920 146.050 44.150 ;
        RECT 140.660 43.170 140.890 43.460 ;
        RECT 141.050 43.440 146.050 43.670 ;
        RECT 146.210 43.650 146.440 43.940 ;
        RECT 141.050 42.960 146.050 43.190 ;
        RECT 140.660 42.210 140.890 42.500 ;
        RECT 141.050 42.480 146.050 42.710 ;
        RECT 146.210 42.690 146.440 42.980 ;
        RECT 141.050 42.000 146.050 42.230 ;
        RECT 140.660 41.250 140.890 41.540 ;
        RECT 141.050 41.520 146.050 41.750 ;
        RECT 146.210 41.730 146.440 42.020 ;
        RECT 141.050 41.040 146.050 41.270 ;
        RECT 140.660 40.290 140.890 40.580 ;
        RECT 141.050 40.560 146.050 40.790 ;
        RECT 146.210 40.770 146.440 41.060 ;
        RECT 141.050 40.080 146.050 40.310 ;
        RECT 140.660 39.330 140.890 39.620 ;
        RECT 141.050 39.600 146.050 39.830 ;
        RECT 146.210 39.810 146.440 40.100 ;
        RECT 141.050 39.120 146.050 39.350 ;
        RECT 140.660 38.370 140.890 38.660 ;
        RECT 141.050 38.640 146.050 38.870 ;
        RECT 146.210 38.850 146.440 39.140 ;
        RECT 141.050 38.160 146.050 38.390 ;
        RECT 140.660 37.410 140.890 37.700 ;
        RECT 141.050 37.680 146.050 37.910 ;
        RECT 146.210 37.890 146.440 38.180 ;
        RECT 141.050 37.200 146.050 37.430 ;
        RECT 140.660 36.450 140.890 36.740 ;
        RECT 141.050 36.720 146.050 36.950 ;
        RECT 146.210 36.930 146.440 37.220 ;
        RECT 141.050 36.240 146.050 36.470 ;
        RECT 140.660 35.490 140.890 35.780 ;
        RECT 141.050 35.760 146.050 35.990 ;
        RECT 146.210 35.970 146.440 36.260 ;
        RECT 141.050 35.280 146.050 35.510 ;
        RECT 140.660 34.530 140.890 34.820 ;
        RECT 141.050 34.800 146.050 35.030 ;
        RECT 146.210 35.010 146.440 35.300 ;
        RECT 141.050 34.320 146.050 34.550 ;
        RECT 140.660 33.570 140.890 33.860 ;
        RECT 141.050 33.840 146.050 34.070 ;
        RECT 146.210 34.050 146.440 34.340 ;
        RECT 141.050 33.360 146.050 33.590 ;
        RECT 140.660 32.610 140.890 32.900 ;
        RECT 141.050 32.880 146.050 33.110 ;
        RECT 146.210 33.090 146.440 33.380 ;
        RECT 141.050 32.400 146.050 32.630 ;
        RECT 140.660 31.650 140.890 31.940 ;
        RECT 141.050 31.920 146.050 32.150 ;
        RECT 146.210 32.130 146.440 32.420 ;
        RECT 141.050 31.440 146.050 31.670 ;
        RECT 140.660 30.690 140.890 30.980 ;
        RECT 141.050 30.960 146.050 31.190 ;
        RECT 146.210 31.170 146.440 31.460 ;
        RECT 141.050 30.480 146.050 30.710 ;
        RECT 140.660 29.730 140.890 30.020 ;
        RECT 141.050 30.000 146.050 30.230 ;
        RECT 146.210 30.210 146.440 30.500 ;
        RECT 141.050 29.520 146.050 29.750 ;
        RECT 140.660 28.770 140.890 29.060 ;
        RECT 141.050 29.040 146.050 29.270 ;
        RECT 146.210 29.250 146.440 29.540 ;
        RECT 141.050 28.560 146.050 28.790 ;
        RECT 140.660 27.810 140.890 28.100 ;
        RECT 141.050 28.080 146.050 28.310 ;
        RECT 146.210 28.290 146.440 28.580 ;
        RECT 141.050 27.600 146.050 27.830 ;
        RECT 140.660 26.850 140.890 27.140 ;
        RECT 141.050 27.120 146.050 27.350 ;
        RECT 146.210 27.330 146.440 27.620 ;
        RECT 141.050 26.640 146.050 26.870 ;
        RECT 140.660 25.890 140.890 26.180 ;
        RECT 141.050 26.160 146.050 26.390 ;
        RECT 146.210 26.370 146.440 26.660 ;
        RECT 141.050 25.680 146.050 25.910 ;
        RECT 140.660 24.930 140.890 25.220 ;
        RECT 141.050 25.200 146.050 25.430 ;
        RECT 146.210 25.410 146.440 25.700 ;
        RECT 141.050 24.720 146.050 24.950 ;
        RECT 140.660 23.970 140.890 24.260 ;
        RECT 141.050 24.240 146.050 24.470 ;
        RECT 146.210 24.450 146.440 24.740 ;
        RECT 141.050 23.760 146.050 23.990 ;
        RECT 140.660 23.010 140.890 23.300 ;
        RECT 141.050 23.280 146.050 23.510 ;
        RECT 146.210 23.490 146.440 23.780 ;
        RECT 149.000 23.210 149.460 23.440 ;
        RECT 149.790 23.210 150.250 23.440 ;
        RECT 150.580 23.210 151.040 23.440 ;
        RECT 151.370 23.210 151.830 23.440 ;
        RECT 152.160 23.210 152.620 23.440 ;
        RECT 152.950 23.210 153.410 23.440 ;
        RECT 153.740 23.210 154.200 23.440 ;
        RECT 154.530 23.210 154.990 23.440 ;
        RECT 155.320 23.210 155.780 23.440 ;
        RECT 156.110 23.210 156.570 23.440 ;
        RECT 156.900 23.210 157.360 23.440 ;
        RECT 157.690 23.210 158.150 23.440 ;
        RECT 158.480 23.210 158.940 23.440 ;
        RECT 159.270 23.210 159.730 23.440 ;
        RECT 160.060 23.210 160.520 23.440 ;
        RECT 160.850 23.210 161.310 23.440 ;
        RECT 161.640 23.210 162.100 23.440 ;
        RECT 162.430 23.210 162.890 23.440 ;
        RECT 163.220 23.210 163.680 23.440 ;
        RECT 164.010 23.210 164.470 23.440 ;
        RECT 141.050 22.800 146.050 23.030 ;
        RECT 140.660 22.050 140.890 22.340 ;
        RECT 141.050 22.320 146.050 22.550 ;
        RECT 146.210 22.530 146.440 22.820 ;
        RECT 141.050 21.840 146.050 22.070 ;
        RECT 140.660 21.090 140.890 21.380 ;
        RECT 141.050 21.360 146.050 21.590 ;
        RECT 146.210 21.570 146.440 21.860 ;
        RECT 141.050 20.880 146.050 21.110 ;
        RECT 140.660 20.130 140.890 20.420 ;
        RECT 141.050 20.400 146.050 20.630 ;
        RECT 146.210 20.610 146.440 20.900 ;
        RECT 141.050 19.920 146.050 20.150 ;
        RECT 140.660 19.170 140.890 19.460 ;
        RECT 141.050 19.440 146.050 19.670 ;
        RECT 146.210 19.650 146.440 19.940 ;
        RECT 141.050 18.960 146.050 19.190 ;
        RECT 140.660 18.210 140.890 18.500 ;
        RECT 141.050 18.480 146.050 18.710 ;
        RECT 146.210 18.690 146.440 18.980 ;
        RECT 141.050 18.000 146.050 18.230 ;
        RECT 140.660 17.250 140.890 17.540 ;
        RECT 141.050 17.520 146.050 17.750 ;
        RECT 146.210 17.730 146.440 18.020 ;
        RECT 141.050 17.040 146.050 17.270 ;
        RECT 140.660 16.290 140.890 16.580 ;
        RECT 141.050 16.560 146.050 16.790 ;
        RECT 146.210 16.770 146.440 17.060 ;
        RECT 141.050 16.080 146.050 16.310 ;
        RECT 140.660 15.330 140.890 15.620 ;
        RECT 141.050 15.600 146.050 15.830 ;
        RECT 146.210 15.810 146.440 16.100 ;
        RECT 141.050 15.120 146.050 15.350 ;
        RECT 140.660 14.370 140.890 14.660 ;
        RECT 141.050 14.640 146.050 14.870 ;
        RECT 146.210 14.850 146.440 15.140 ;
        RECT 141.050 14.160 146.050 14.390 ;
        RECT 140.660 13.410 140.890 13.700 ;
        RECT 141.050 13.680 146.050 13.910 ;
        RECT 146.210 13.890 146.440 14.180 ;
        RECT 141.050 13.200 146.050 13.430 ;
        RECT 141.050 12.720 146.050 12.950 ;
        RECT 146.210 12.930 146.440 13.220 ;
        RECT 148.720 13.050 148.950 23.050 ;
        RECT 149.510 13.050 149.740 23.050 ;
        RECT 150.300 13.050 150.530 23.050 ;
        RECT 151.090 13.050 151.320 23.050 ;
        RECT 151.880 13.050 152.110 23.050 ;
        RECT 152.670 13.050 152.900 23.050 ;
        RECT 153.460 13.050 153.690 23.050 ;
        RECT 154.250 13.050 154.480 23.050 ;
        RECT 155.040 13.050 155.270 23.050 ;
        RECT 155.830 13.050 156.060 23.050 ;
        RECT 156.620 13.050 156.850 23.050 ;
        RECT 157.410 13.050 157.640 23.050 ;
        RECT 158.200 13.050 158.430 23.050 ;
        RECT 158.990 13.050 159.220 23.050 ;
        RECT 159.780 13.050 160.010 23.050 ;
        RECT 160.570 13.050 160.800 23.050 ;
        RECT 161.360 13.050 161.590 23.050 ;
        RECT 162.150 13.050 162.380 23.050 ;
        RECT 162.940 13.050 163.170 23.050 ;
        RECT 163.730 13.050 163.960 23.050 ;
        RECT 164.520 13.050 164.750 23.050 ;
        RECT 149.000 12.660 149.460 12.890 ;
        RECT 149.790 12.660 150.250 12.890 ;
        RECT 150.580 12.660 151.040 12.890 ;
        RECT 151.370 12.660 151.830 12.890 ;
        RECT 152.160 12.660 152.620 12.890 ;
        RECT 152.950 12.660 153.410 12.890 ;
        RECT 153.740 12.660 154.200 12.890 ;
        RECT 154.530 12.660 154.990 12.890 ;
        RECT 155.320 12.660 155.780 12.890 ;
        RECT 156.110 12.660 156.570 12.890 ;
        RECT 156.900 12.660 157.360 12.890 ;
        RECT 157.690 12.660 158.150 12.890 ;
        RECT 158.480 12.660 158.940 12.890 ;
        RECT 159.270 12.660 159.730 12.890 ;
        RECT 160.060 12.660 160.520 12.890 ;
        RECT 160.850 12.660 161.310 12.890 ;
        RECT 161.640 12.660 162.100 12.890 ;
        RECT 162.430 12.660 162.890 12.890 ;
        RECT 163.220 12.660 163.680 12.890 ;
        RECT 164.010 12.660 164.470 12.890 ;
      LAYER met2 ;
        RECT 118.640 181.000 119.640 224.760 ;
        RECT 121.400 181.000 122.400 224.760 ;
        RECT 124.160 181.000 125.160 224.760 ;
        RECT 126.920 181.000 127.920 224.760 ;
        RECT 129.680 181.000 130.680 224.760 ;
        RECT 132.440 181.000 133.440 224.760 ;
        RECT 135.200 181.000 136.200 224.760 ;
        RECT 137.960 181.000 138.960 224.760 ;
        RECT 118.140 180.000 186.000 181.000 ;
        RECT 173.500 96.000 174.500 180.000 ;
        RECT 184.500 96.000 185.500 180.000 ;
      LAYER met3 ;
        RECT 2.000 196.800 25.160 218.200 ;
        RECT 28.490 196.800 51.650 218.200 ;
        RECT 54.980 196.800 78.140 218.200 ;
        RECT 81.470 196.800 104.630 218.200 ;
        RECT 107.960 196.800 131.120 218.200 ;
        RECT 134.450 196.800 157.610 218.200 ;
        RECT 160.940 196.800 184.100 218.200 ;
        RECT 187.430 196.800 210.590 218.200 ;
        RECT 2.000 173.800 25.160 195.200 ;
        RECT 28.490 173.800 51.650 195.200 ;
        RECT 54.980 173.800 78.140 195.200 ;
        RECT 81.470 173.800 104.630 195.200 ;
        RECT 107.960 173.800 131.120 195.200 ;
        RECT 134.450 173.800 157.610 195.200 ;
        RECT 160.940 173.800 184.100 195.200 ;
        RECT 187.430 173.800 210.590 195.200 ;
        RECT 212.000 173.000 239.460 198.700 ;
        RECT 242.000 192.000 274.160 222.400 ;
        RECT 275.000 173.000 302.470 198.710 ;
        RECT 306.000 192.000 334.260 218.500 ;
        RECT 142.000 55.000 154.160 65.400 ;
        RECT 173.000 57.540 193.050 75.830 ;
        RECT 173.000 42.890 187.810 55.940 ;
        RECT 173.000 31.950 184.100 41.290 ;
        RECT 173.000 17.160 179.630 22.030 ;
        RECT 173.000 12.000 178.320 15.560 ;
      LAYER met4 ;
        RECT 12.440 217.805 12.960 219.000 ;
        RECT 2.395 197.195 23.005 217.805 ;
        RECT 12.440 194.805 12.960 197.195 ;
        RECT 2.395 174.195 23.005 194.805 ;
        RECT 12.440 173.000 12.960 174.195 ;
        RECT 24.640 173.000 25.160 219.000 ;
        RECT 38.930 217.805 39.450 219.000 ;
        RECT 28.885 197.195 49.495 217.805 ;
        RECT 38.930 194.805 39.450 197.195 ;
        RECT 28.885 174.195 49.495 194.805 ;
        RECT 38.930 173.000 39.450 174.195 ;
        RECT 51.130 173.000 51.650 219.000 ;
        RECT 65.420 217.805 65.940 219.000 ;
        RECT 55.375 197.195 75.985 217.805 ;
        RECT 65.420 194.805 65.940 197.195 ;
        RECT 55.375 174.195 75.985 194.805 ;
        RECT 65.420 173.000 65.940 174.195 ;
        RECT 77.620 173.000 78.140 219.000 ;
        RECT 91.910 217.805 92.430 219.000 ;
        RECT 81.865 197.195 102.475 217.805 ;
        RECT 91.910 194.805 92.430 197.195 ;
        RECT 81.865 174.195 102.475 194.805 ;
        RECT 91.910 173.000 92.430 174.195 ;
        RECT 104.110 173.000 104.630 219.000 ;
        RECT 118.400 217.805 118.920 219.000 ;
        RECT 108.355 197.195 128.965 217.805 ;
        RECT 118.400 194.805 118.920 197.195 ;
        RECT 108.355 174.195 128.965 194.805 ;
        RECT 118.400 173.000 118.920 174.195 ;
        RECT 130.600 173.000 131.120 219.000 ;
        RECT 144.890 217.805 145.410 219.000 ;
        RECT 134.845 197.195 155.455 217.805 ;
        RECT 144.890 194.805 145.410 197.195 ;
        RECT 134.845 174.195 155.455 194.805 ;
        RECT 144.890 173.000 145.410 174.195 ;
        RECT 157.090 173.000 157.610 219.000 ;
        RECT 183.580 173.000 184.100 219.000 ;
        RECT 197.870 217.805 198.390 219.000 ;
        RECT 187.825 197.195 208.435 217.805 ;
        RECT 197.870 194.805 198.390 197.195 ;
        RECT 187.825 174.195 208.435 194.805 ;
        RECT 197.870 173.000 198.390 174.195 ;
        RECT 210.070 173.000 210.590 219.000 ;
        RECT 212.395 173.395 237.305 198.305 ;
        RECT 238.960 173.060 239.440 198.640 ;
        RECT 242.395 192.395 272.005 222.005 ;
        RECT 273.660 192.060 274.140 222.340 ;
        RECT 275.395 173.395 300.315 198.315 ;
        RECT 301.970 173.060 302.450 198.650 ;
        RECT 306.395 192.395 332.105 218.105 ;
        RECT 333.760 192.060 334.240 218.440 ;
        RECT 140.395 95.395 162.005 117.005 ;
        RECT 140.395 70.395 162.005 92.005 ;
        RECT 142.395 55.395 152.005 65.005 ;
        RECT 153.660 55.060 154.140 65.340 ;
        RECT 173.395 57.935 190.895 75.435 ;
        RECT 192.550 57.600 193.030 75.770 ;
        RECT 142.395 30.395 162.205 50.205 ;
        RECT 173.395 43.285 185.655 55.545 ;
        RECT 187.310 42.950 187.790 55.880 ;
        RECT 173.395 32.345 181.945 40.895 ;
        RECT 183.600 32.010 184.080 41.230 ;
        RECT 173.395 24.025 179.325 29.955 ;
        RECT 173.395 17.555 177.475 21.635 ;
        RECT 179.130 17.220 179.610 21.970 ;
        RECT 173.395 12.395 176.165 15.165 ;
        RECT 177.820 12.060 178.300 15.500 ;
  END
END tt_um_thomas_ep_sensor
END LIBRARY

